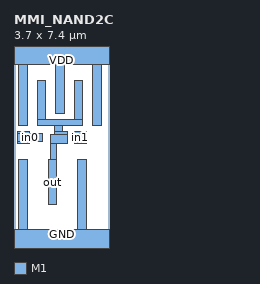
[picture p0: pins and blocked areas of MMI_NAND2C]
MACRO MMI_NAND2C
	CLASS CORE ;
	FOREIGN MMI_NAND2C 0 0 ;
	SIZE 3.7 BY 7.4 ;
	SYMMETRY X Y ;
	SITE CORE1 ;
	PIN out
		DIRECTION output ;
		USE SIGNAL ;
		PORT
			LAYER M1 ;
			RECT 0.9 4.765 1.24 6.295 ;
			LAYER M1 ;
			RECT 2.34 4.765 2.68 6.295 ;
			LAYER M1 ;
			RECT 0.9 4.535 2.68 4.765 ;
			LAYER M1 ;
			RECT 1.565 4.295 1.905 4.535 ;
			LAYER M1 ;
			RECT 1.565 4.185 2.075 4.295 ;
			LAYER M1 ;
			RECT 1.44 3.845 2.075 4.185 ;
			LAYER M1 ;
			RECT 1.44 3.215 1.67 3.845 ;
			LAYER M1 ;
			RECT 1.33 1.455 1.67 3.215 ;
		END
		AntennaDiffArea 2.9808 ;
	END out
	PIN in1
		DIRECTION input ;
		USE SIGNAL ;
		PORT
			LAYER M1 ;
			RECT 2.365 4.24 2.815 4.295 ;
			LAYER M1 ;
			RECT 2.305 3.9 2.815 4.24 ;
			LAYER M1 ;
			RECT 2.365 3.845 2.815 3.9 ;
		END
		AntennaGateArea 1.3248 ;
	END in1
	PIN GND
		DIRECTION inout ;
		USE GROUND ;
		PORT
			LAYER M1 ;
			RECT 0.18 0.5 0.52 3.215 ;
			LAYER M1 ;
			RECT 2.48 0.5 2.82 3.215 ;
			LAYER M1 ;
			RECT 0 -0.5 3.7 0.5 ;
		END
	END GND
	PIN VDD
		DIRECTION inout ;
		USE POWER ;
		PORT
			LAYER M1 ;
			RECT 0 6.9 3.7 7.9 ;
			LAYER M1 ;
			RECT 0.18 4.535 0.52 6.9 ;
			LAYER M1 ;
			RECT 1.62 5.015 1.96 6.9 ;
			LAYER M1 ;
			RECT 3.06 4.535 3.4 6.9 ;
		END
	END VDD
	PIN in0
		DIRECTION input ;
		USE SIGNAL ;
		PORT
			LAYER M1 ;
			RECT 0.145 4.24 0.595 4.295 ;
			LAYER M1 ;
			RECT 0.145 3.9 1.12 4.24 ;
			LAYER M1 ;
			RECT 0.145 3.845 0.595 3.9 ;
		END
		AntennaGateArea 1.3248 ;
	END in0
	OBS
	END
END MMI_NAND2C
